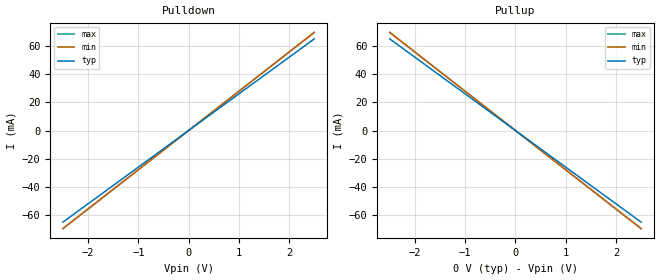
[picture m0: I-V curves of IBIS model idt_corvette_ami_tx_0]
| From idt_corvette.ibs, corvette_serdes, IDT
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|   model   idt_corvette_ami_tx_0
[Model] idt_corvette_ami_tx_0
Model_type Output
C_comp 400f 400f 400f
Cref = 0
[Model Spec]
Vmeas 0. 0. 0.
Vref 0. 0. 0.
[Temperature Range]  25 100 0
[Voltage Range] 0.0001 0.0001 0.0001
[Algorithmic Model]
Executable Windows_VisualStudio5_32 idt_corvette_tx.dll   idt_corvette_tx.ami
Executable Windows_ver_64   idt_corvette_tx_64.dll   idt_corvette_tx.ami
Executable Linux_gcc4.1.2_32   idt_corvette_tx.linux.so   idt_corvette_tx.ami
Executable Linux_gcc3.2.3_64   idt_corvette_tx_64.linux.so idt_corvette_tx.ami
[End Algorithmic Model]
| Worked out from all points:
|   slope of the pulldown table from 0 to 0 V, typ, clamps not added: 38.6 ohm
|   slope of the pullup table from 0 to 0 V, typ, clamps not added: 38.6 ohm
[Pulldown]
-2.5V     -64.85mA   -69.44mA   -69.44mA
0V        0A         0A         0A
2.5V      64.85mA    69.44mA    69.44mA
[Pullup]
-2.5V     64.85mA    69.44mA    69.44mA
0V        0A         0A         0A
2.5V      -64.85mA   -69.44mA   -69.44mA
[Ramp]
dV/dt_r 0.0001/21.588p 0.0001/20.16p 0.0001/20.16p
dV/dt_f 0.0001/21.588p 0.0001/20.16p 0.0001/20.16p
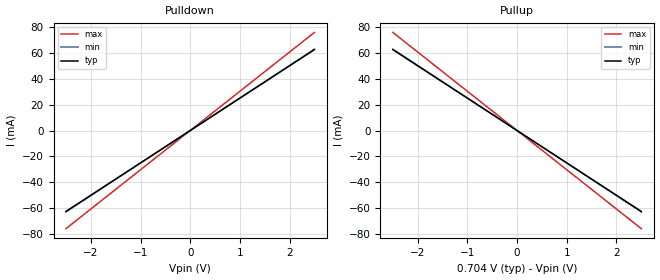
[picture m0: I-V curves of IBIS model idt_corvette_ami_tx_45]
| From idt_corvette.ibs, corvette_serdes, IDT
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|   model   idt_corvette_ami_tx_45
[Model] idt_corvette_ami_tx_45
Model_type Output
C_comp 400f 400f 400f
Cref = 0
[Model Spec]
Vmeas 0. 0. 0.
Vref 0. 0. 0.
[Temperature Range]  25 100 0
[Voltage Range] .704 .694 .621
[Algorithmic Model]
Executable Windows_VisualStudio5_32 idt_corvette_tx.dll   idt_corvette_tx.ami
Executable Windows_ver_64   idt_corvette_tx_64.dll   idt_corvette_tx.ami
Executable Linux_gcc4.1.2_32   idt_corvette_tx.linux.so   idt_corvette_tx.ami
Executable Linux_gcc3.2.3_64   idt_corvette_tx_64.linux.so idt_corvette_tx.ami
[End Algorithmic Model]
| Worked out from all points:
|   slope of the pulldown table from 0 to 0.106 V, typ, clamps not added: 40 ohm
|   slope of the pullup table from 0 to 0.106 V, typ, clamps not added: 40 ohm
[Pulldown]
-2.5V     -62.5mA    -62.89mA   -75.81mA
0V        0A         0A         0A
2.5V      62.5mA     62.89mA    75.81mA
[Pullup]
-2.5V     62.5mA     62.89mA    75.81mA
0V        0A         0A         0A
2.5V      -62.5mA    -62.89mA   -75.81mA
[Ramp]
dV/dt_r .235/22.4p .232/22.26p .225/18.467p
dV/dt_f .235/22.4p .232/22.26p .225/18.467p
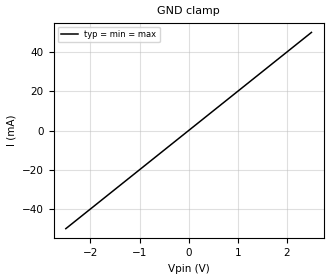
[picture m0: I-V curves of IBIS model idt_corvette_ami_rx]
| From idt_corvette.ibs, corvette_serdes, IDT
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|   MODEL: idt_corvette_ami_rx
[Model]   idt_corvette_ami_rx
Model_type Input
Vinl = .05
Vinh = .05
|   typ   min   max
C_comp   0.95pF 0.95pF 0.95pF
[Model Spec]
[Algorithmic Model]
Executable Windows_VisualStudio5_32 idt_corvette_rx.dll   idt_corvette_rx.ami
Executable Windows_ver_64   idt_corvette_rx_64.dll   idt_corvette_rx.ami
Executable Linux_gcc4.1.2_32   idt_corvette_rx.linux.so   idt_corvette_rx.ami
Executable Linux_gcc3.2.3_64   idt_corvette_rx_64.linux.so idt_corvette_rx.ami
[End Algorithmic Model]
[Temperature Range]  25   100  0
[Voltage Range]   1.0  1.0  1.0
[GND Clamp]
-2.5V     -50mA      -50mA      -50mA
0V        0A         0A         0A
2.5V      50mA       50mA       50mA
